VERSION 5.7 ;
BUSBITCHARS "[]" ;
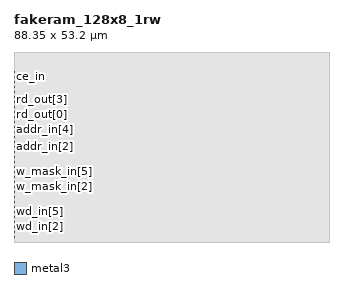
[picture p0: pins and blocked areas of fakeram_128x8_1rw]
MACRO fakeram_128x8_1rw
  FOREIGN fakeram_128x8_1rw 0 0 ;
  SYMMETRY X Y R90 ;
  SIZE 88.350 BY 53.200 ;
  CLASS BLOCK ;
  PIN wd_in[0]
    DIRECTION INPUT ;
    USE SIGNAL ;
    SHAPE ABUTMENT ;
    PORT
      LAYER metal3 ;
      RECT 0.000 1.400 0.140 1.540 ;
    END
  END wd_in[0]
  PIN wd_in[1]
    DIRECTION INPUT ;
    USE SIGNAL ;
    SHAPE ABUTMENT ;
    PORT
      LAYER metal3 ;
      RECT 0.000 2.800 0.140 2.940 ;
    END
  END wd_in[1]
  PIN wd_in[2]
    DIRECTION INPUT ;
    USE SIGNAL ;
    SHAPE ABUTMENT ;
    PORT
      LAYER metal3 ;
      RECT 0.000 4.200 0.140 4.340 ;
    END
  END wd_in[2]
  PIN wd_in[3]
    DIRECTION INPUT ;
    USE SIGNAL ;
    SHAPE ABUTMENT ;
    PORT
      LAYER metal3 ;
      RECT 0.000 5.600 0.140 5.740 ;
    END
  END wd_in[3]
  PIN wd_in[4]
    DIRECTION INPUT ;
    USE SIGNAL ;
    SHAPE ABUTMENT ;
    PORT
      LAYER metal3 ;
      RECT 0.000 7.000 0.140 7.140 ;
    END
  END wd_in[4]
  PIN wd_in[5]
    DIRECTION INPUT ;
    USE SIGNAL ;
    SHAPE ABUTMENT ;
    PORT
      LAYER metal3 ;
      RECT 0.000 8.400 0.140 8.540 ;
    END
  END wd_in[5]
  PIN wd_in[6]
    DIRECTION INPUT ;
    USE SIGNAL ;
    SHAPE ABUTMENT ;
    PORT
      LAYER metal3 ;
      RECT 0.000 9.800 0.140 9.940 ;
    END
  END wd_in[6]
  PIN wd_in[7]
    DIRECTION INPUT ;
    USE SIGNAL ;
    SHAPE ABUTMENT ;
    PORT
      LAYER metal3 ;
      RECT 0.000 11.200 0.140 11.340 ;
    END
  END wd_in[7]
  PIN w_mask_in[0]
    DIRECTION INPUT ;
    USE SIGNAL ;
    SHAPE ABUTMENT ;
    PORT
      LAYER metal3 ;
      RECT 0.000 12.600 0.140 12.740 ;
    END
  END w_mask_in[0]
  PIN w_mask_in[1]
    DIRECTION INPUT ;
    USE SIGNAL ;
    SHAPE ABUTMENT ;
    PORT
      LAYER metal3 ;
      RECT 0.000 14.000 0.140 14.140 ;
    END
  END w_mask_in[1]
  PIN w_mask_in[2]
    DIRECTION INPUT ;
    USE SIGNAL ;
    SHAPE ABUTMENT ;
    PORT
      LAYER metal3 ;
      RECT 0.000 15.400 0.140 15.540 ;
    END
  END w_mask_in[2]
  PIN w_mask_in[3]
    DIRECTION INPUT ;
    USE SIGNAL ;
    SHAPE ABUTMENT ;
    PORT
      LAYER metal3 ;
      RECT 0.000 16.800 0.140 16.940 ;
    END
  END w_mask_in[3]
  PIN w_mask_in[4]
    DIRECTION INPUT ;
    USE SIGNAL ;
    SHAPE ABUTMENT ;
    PORT
      LAYER metal3 ;
      RECT 0.000 18.200 0.140 18.340 ;
    END
  END w_mask_in[4]
  PIN w_mask_in[5]
    DIRECTION INPUT ;
    USE SIGNAL ;
    SHAPE ABUTMENT ;
    PORT
      LAYER metal3 ;
      RECT 0.000 19.600 0.140 19.740 ;
    END
  END w_mask_in[5]
  PIN w_mask_in[6]
    DIRECTION INPUT ;
    USE SIGNAL ;
    SHAPE ABUTMENT ;
    PORT
      LAYER metal3 ;
      RECT 0.000 21.000 0.140 21.140 ;
    END
  END w_mask_in[6]
  PIN w_mask_in[7]
    DIRECTION INPUT ;
    USE SIGNAL ;
    SHAPE ABUTMENT ;
    PORT
      LAYER metal3 ;
      RECT 0.000 22.400 0.140 22.540 ;
    END
  END w_mask_in[7]
  PIN addr_in[0]
    DIRECTION INPUT ;
    USE SIGNAL ;
    SHAPE ABUTMENT ;
    PORT
      LAYER metal3 ;
      RECT 0.000 23.800 0.140 23.940 ;
    END
  END addr_in[0]
  PIN addr_in[1]
    DIRECTION INPUT ;
    USE SIGNAL ;
    SHAPE ABUTMENT ;
    PORT
      LAYER metal3 ;
      RECT 0.000 25.200 0.140 25.340 ;
    END
  END addr_in[1]
  PIN addr_in[2]
    DIRECTION INPUT ;
    USE SIGNAL ;
    SHAPE ABUTMENT ;
    PORT
      LAYER metal3 ;
      RECT 0.000 26.600 0.140 26.740 ;
    END
  END addr_in[2]
  PIN addr_in[3]
    DIRECTION INPUT ;
    USE SIGNAL ;
    SHAPE ABUTMENT ;
    PORT
      LAYER metal3 ;
      RECT 0.000 28.000 0.140 28.140 ;
    END
  END addr_in[3]
  PIN addr_in[4]
    DIRECTION INPUT ;
    USE SIGNAL ;
    SHAPE ABUTMENT ;
    PORT
      LAYER metal3 ;
      RECT 0.000 29.400 0.140 29.540 ;
    END
  END addr_in[4]
  PIN addr_in[5]
    DIRECTION INPUT ;
    USE SIGNAL ;
    SHAPE ABUTMENT ;
    PORT
      LAYER metal3 ;
      RECT 0.000 30.800 0.140 30.940 ;
    END
  END addr_in[5]
  PIN addr_in[6]
    DIRECTION INPUT ;
    USE SIGNAL ;
    SHAPE ABUTMENT ;
    PORT
      LAYER metal3 ;
      RECT 0.000 32.200 0.140 32.340 ;
    END
  END addr_in[6]
  PIN rd_out[0]
    DIRECTION OUTPUT ;
    USE SIGNAL ;
    SHAPE ABUTMENT ;
    PORT
      LAYER metal3 ;
      RECT 0.000 33.600 0.140 33.740 ;
    END
  END rd_out[0]
  PIN rd_out[1]
    DIRECTION OUTPUT ;
    USE SIGNAL ;
    SHAPE ABUTMENT ;
    PORT
      LAYER metal3 ;
      RECT 0.000 35.000 0.140 35.140 ;
    END
  END rd_out[1]
  PIN rd_out[2]
    DIRECTION OUTPUT ;
    USE SIGNAL ;
    SHAPE ABUTMENT ;
    PORT
      LAYER metal3 ;
      RECT 0.000 36.400 0.140 36.540 ;
    END
  END rd_out[2]
  PIN rd_out[3]
    DIRECTION OUTPUT ;
    USE SIGNAL ;
    SHAPE ABUTMENT ;
    PORT
      LAYER metal3 ;
      RECT 0.000 37.800 0.140 37.940 ;
    END
  END rd_out[3]
  PIN rd_out[4]
    DIRECTION OUTPUT ;
    USE SIGNAL ;
    SHAPE ABUTMENT ;
    PORT
      LAYER metal3 ;
      RECT 0.000 39.200 0.140 39.340 ;
    END
  END rd_out[4]
  PIN rd_out[5]
    DIRECTION OUTPUT ;
    USE SIGNAL ;
    SHAPE ABUTMENT ;
    PORT
      LAYER metal3 ;
      RECT 0.000 40.600 0.140 40.740 ;
    END
  END rd_out[5]
  PIN rd_out[6]
    DIRECTION OUTPUT ;
    USE SIGNAL ;
    SHAPE ABUTMENT ;
    PORT
      LAYER metal3 ;
      RECT 0.000 42.000 0.140 42.140 ;
    END
  END rd_out[6]
  PIN rd_out[7]
    DIRECTION OUTPUT ;
    USE SIGNAL ;
    SHAPE ABUTMENT ;
    PORT
      LAYER metal3 ;
      RECT 0.000 43.400 0.140 43.540 ;
    END
  END rd_out[7]
  PIN clk
    DIRECTION INPUT ;
    USE SIGNAL ;
    SHAPE ABUTMENT ;
    PORT
      LAYER metal3 ;
      RECT 0.000 44.800 0.140 44.940 ;
    END
  END clk
  PIN ce_in
    DIRECTION INPUT ;
    USE SIGNAL ;
    SHAPE ABUTMENT ;
    PORT
      LAYER metal3 ;
      RECT 0.000 46.200 0.140 46.340 ;
    END
  END ce_in
  PIN we_in
    DIRECTION INPUT ;
    USE SIGNAL ;
    SHAPE ABUTMENT ;
    PORT
      LAYER metal3 ;
      RECT 0.000 47.600 0.140 47.740 ;
    END
  END we_in
  OBS
    LAYER metal1 ;
      RECT 0.000 0.000 88.350 53.200 ;
    LAYER metal2 ;
      RECT 0.000 0.000 88.350 53.200 ;
    LAYER metal3 ;
      RECT 0.000 0.000 88.350 53.200 ;
    LAYER metal4 ;
      RECT 0.000 0.000 88.350 53.200 ;
  END
END fakeram_128x8_1rw
END LIBRARY
